One B-rep face of a CAD part: STEP entity #81894.
In plain terms, the planar face has unit normal (0, 0, 1).
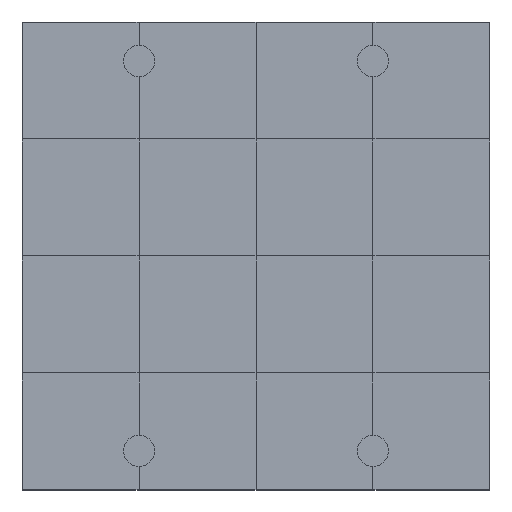
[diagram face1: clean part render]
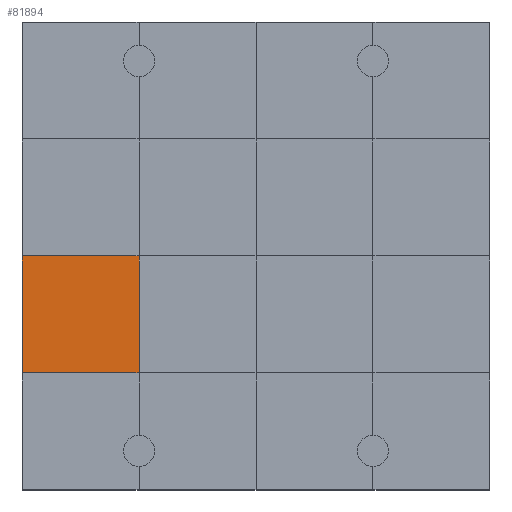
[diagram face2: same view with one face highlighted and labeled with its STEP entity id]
Its self-contained STEP definition (entity closure, numbers rounded to 3 decimals):
#81444 = VERTEX_POINT('',#81445);
#81445 = CARTESIAN_POINT('',(0.,3.,1.2));
#81459 = PLANE('',#81460);
#81460 = AXIS2_PLACEMENT_3D('',#81461,#81462,#81463);
#81461 = CARTESIAN_POINT('',(0.,3.,0.));
#81462 = DIRECTION('',(1.,0.,-0.));
#81463 = DIRECTION('',(0.,0.,1.));
#81485 = PLANE('',#81486);
#81486 = AXIS2_PLACEMENT_3D('',#81487,#81488,#81489);
#81487 = CARTESIAN_POINT('',(0.,0.,1.2));
#81488 = DIRECTION('',(0.,0.,1.));
#81489 = DIRECTION('',(1.,0.,-0.));
#81636 = VERTEX_POINT('',#81637);
#81637 = CARTESIAN_POINT('',(3.,3.,1.2));
#81658 = EDGE_CURVE('',#81444,#81636,#81659,.T.);
#81659 = SURFACE_CURVE('',#81660,(#81664,#81671),.PCURVE_S1.);
#81660 = LINE('',#81661,#81662);
#81661 = CARTESIAN_POINT('',(0.,3.,1.2));
#81662 = VECTOR('',#81663,1.);
#81663 = DIRECTION('',(1.,0.,-0.));
#81664 = PCURVE('',#81485,#81665);
#81665 = DEFINITIONAL_REPRESENTATION('',(#81666),#81670);
#81666 = LINE('',#81667,#81668);
#81667 = CARTESIAN_POINT('',(0.,3.));
#81668 = VECTOR('',#81669,1.);
#81669 = DIRECTION('',(1.,0.));
#81670 = ( GEOMETRIC_REPRESENTATION_CONTEXT(2) 
PARAMETRIC_REPRESENTATION_CONTEXT() REPRESENTATION_CONTEXT('2D SPACE',''
  ) );
#81671 = PCURVE('',#81672,#81677);
#81672 = PLANE('',#81673);
#81673 = AXIS2_PLACEMENT_3D('',#81674,#81675,#81676);
#81674 = CARTESIAN_POINT('',(0.,3.,1.2));
#81675 = DIRECTION('',(0.,0.,1.));
#81676 = DIRECTION('',(1.,0.,-0.));
#81677 = DEFINITIONAL_REPRESENTATION('',(#81678),#81682);
#81678 = LINE('',#81679,#81680);
#81679 = CARTESIAN_POINT('',(0.,0.));
#81680 = VECTOR('',#81681,1.);
#81681 = DIRECTION('',(1.,0.));
#81682 = ( GEOMETRIC_REPRESENTATION_CONTEXT(2) 
PARAMETRIC_REPRESENTATION_CONTEXT() REPRESENTATION_CONTEXT('2D SPACE',''
  ) );
#81717 = VERTEX_POINT('',#81718);
#81718 = CARTESIAN_POINT('',(0.,6.,1.2));
#81744 = EDGE_CURVE('',#81444,#81717,#81745,.T.);
#81745 = SURFACE_CURVE('',#81746,(#81750,#81757),.PCURVE_S1.);
#81746 = LINE('',#81747,#81748);
#81747 = CARTESIAN_POINT('',(0.,3.,1.2));
#81748 = VECTOR('',#81749,1.);
#81749 = DIRECTION('',(-0.,1.,0.));
#81750 = PCURVE('',#81459,#81751);
#81751 = DEFINITIONAL_REPRESENTATION('',(#81752),#81756);
#81752 = LINE('',#81753,#81754);
#81753 = CARTESIAN_POINT('',(1.2,0.));
#81754 = VECTOR('',#81755,1.);
#81755 = DIRECTION('',(0.,-1.));
#81756 = ( GEOMETRIC_REPRESENTATION_CONTEXT(2) 
PARAMETRIC_REPRESENTATION_CONTEXT() REPRESENTATION_CONTEXT('2D SPACE',''
  ) );
#81757 = PCURVE('',#81672,#81758);
#81758 = DEFINITIONAL_REPRESENTATION('',(#81759),#81763);
#81759 = LINE('',#81760,#81761);
#81760 = CARTESIAN_POINT('',(0.,0.));
#81761 = VECTOR('',#81762,1.);
#81762 = DIRECTION('',(0.,1.));
#81763 = ( GEOMETRIC_REPRESENTATION_CONTEXT(2) 
PARAMETRIC_REPRESENTATION_CONTEXT() REPRESENTATION_CONTEXT('2D SPACE',''
  ) );
#81894 = ADVANCED_FACE('',(#81895),#81672,.T.);
#81895 = FACE_BOUND('',#81896,.T.);
#81896 = EDGE_LOOP('',(#81897,#81898,#81899,#81927));
#81897 = ORIENTED_EDGE('',*,*,#81744,.F.);
#81898 = ORIENTED_EDGE('',*,*,#81658,.T.);
#81899 = ORIENTED_EDGE('',*,*,#81900,.T.);
#81900 = EDGE_CURVE('',#81636,#81901,#81903,.T.);
#81901 = VERTEX_POINT('',#81902);
#81902 = CARTESIAN_POINT('',(3.,6.,1.2));
#81903 = SURFACE_CURVE('',#81904,(#81908,#81915),.PCURVE_S1.);
#81904 = LINE('',#81905,#81906);
#81905 = CARTESIAN_POINT('',(3.,3.,1.2));
#81906 = VECTOR('',#81907,1.);
#81907 = DIRECTION('',(-0.,1.,0.));
#81908 = PCURVE('',#81672,#81909);
#81909 = DEFINITIONAL_REPRESENTATION('',(#81910),#81914);
#81910 = LINE('',#81911,#81912);
#81911 = CARTESIAN_POINT('',(3.,0.));
#81912 = VECTOR('',#81913,1.);
#81913 = DIRECTION('',(0.,1.));
#81914 = ( GEOMETRIC_REPRESENTATION_CONTEXT(2) 
PARAMETRIC_REPRESENTATION_CONTEXT() REPRESENTATION_CONTEXT('2D SPACE',''
  ) );
#81915 = PCURVE('',#81916,#81921);
#81916 = PLANE('',#81917);
#81917 = AXIS2_PLACEMENT_3D('',#81918,#81919,#81920);
#81918 = CARTESIAN_POINT('',(3.,3.,1.2));
#81919 = DIRECTION('',(0.,0.,1.));
#81920 = DIRECTION('',(1.,0.,-0.));
#81921 = DEFINITIONAL_REPRESENTATION('',(#81922),#81926);
#81922 = LINE('',#81923,#81924);
#81923 = CARTESIAN_POINT('',(0.,0.));
#81924 = VECTOR('',#81925,1.);
#81925 = DIRECTION('',(0.,1.));
#81926 = ( GEOMETRIC_REPRESENTATION_CONTEXT(2) 
PARAMETRIC_REPRESENTATION_CONTEXT() REPRESENTATION_CONTEXT('2D SPACE',''
  ) );
#81927 = ORIENTED_EDGE('',*,*,#81928,.F.);
#81928 = EDGE_CURVE('',#81717,#81901,#81929,.T.);
#81929 = SURFACE_CURVE('',#81930,(#81934,#81941),.PCURVE_S1.);
#81930 = LINE('',#81931,#81932);
#81931 = CARTESIAN_POINT('',(0.,6.,1.2));
#81932 = VECTOR('',#81933,1.);
#81933 = DIRECTION('',(1.,0.,-0.));
#81934 = PCURVE('',#81672,#81935);
#81935 = DEFINITIONAL_REPRESENTATION('',(#81936),#81940);
#81936 = LINE('',#81937,#81938);
#81937 = CARTESIAN_POINT('',(0.,3.));
#81938 = VECTOR('',#81939,1.);
#81939 = DIRECTION('',(1.,0.));
#81940 = ( GEOMETRIC_REPRESENTATION_CONTEXT(2) 
PARAMETRIC_REPRESENTATION_CONTEXT() REPRESENTATION_CONTEXT('2D SPACE',''
  ) );
#81941 = PCURVE('',#81942,#81947);
#81942 = PLANE('',#81943);
#81943 = AXIS2_PLACEMENT_3D('',#81944,#81945,#81946);
#81944 = CARTESIAN_POINT('',(0.,6.,1.2));
#81945 = DIRECTION('',(0.,0.,1.));
#81946 = DIRECTION('',(1.,0.,-0.));
#81947 = DEFINITIONAL_REPRESENTATION('',(#81948),#81952);
#81948 = LINE('',#81949,#81950);
#81949 = CARTESIAN_POINT('',(0.,0.));
#81950 = VECTOR('',#81951,1.);
#81951 = DIRECTION('',(1.,0.));
#81952 = ( GEOMETRIC_REPRESENTATION_CONTEXT(2) 
PARAMETRIC_REPRESENTATION_CONTEXT() REPRESENTATION_CONTEXT('2D SPACE',''
  ) );
